# Generated by FakeRAM 2.0
VERSION 5.7 ;
BUSBITCHARS "[]" ;
PROPERTYDEFINITIONS
  MACRO width INTEGER ;
  MACRO depth INTEGER ;
  MACRO banks INTEGER ;
END PROPERTYDEFINITIONS
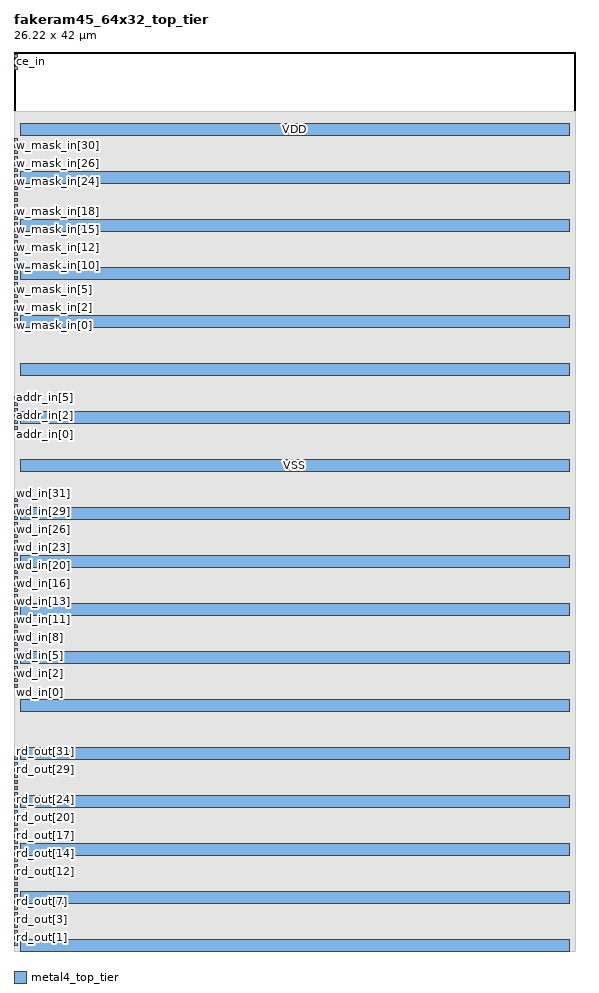
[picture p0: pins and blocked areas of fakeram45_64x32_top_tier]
MACRO fakeram45_64x32_top_tier
  PROPERTY width 32 ;
  PROPERTY depth 64 ;
  PROPERTY banks 1 ;
  FOREIGN fakeram45_64x32_top_tier 0 0 ;
  SYMMETRY X Y R90 ;
  SIZE 26.220 BY 42.0 ;
  CLASS BLOCK ;
  PIN rd_out[0]
    DIRECTION OUTPUT ;
    USE SIGNAL ;
    SHAPE ABUTMENT ;
    PORT
      LAYER metal4_top_tier ;
      RECT 0.000 0.280 0.140 0.420 ;
    END
  END rd_out[0]
  PIN rd_out[1]
    DIRECTION OUTPUT ;
    USE SIGNAL ;
    SHAPE ABUTMENT ;
    PORT
      LAYER metal4_top_tier ;
      RECT 0.000 0.560 0.140 0.700 ;
    END
  END rd_out[1]
  PIN rd_out[2]
    DIRECTION OUTPUT ;
    USE SIGNAL ;
    SHAPE ABUTMENT ;
    PORT
      LAYER metal4_top_tier ;
      RECT 0.000 0.840 0.140 0.980 ;
    END
  END rd_out[2]
  PIN rd_out[3]
    DIRECTION OUTPUT ;
    USE SIGNAL ;
    SHAPE ABUTMENT ;
    PORT
      LAYER metal4_top_tier ;
      RECT 0.000 1.120 0.140 1.260 ;
    END
  END rd_out[3]
  PIN rd_out[4]
    DIRECTION OUTPUT ;
    USE SIGNAL ;
    SHAPE ABUTMENT ;
    PORT
      LAYER metal4_top_tier ;
      RECT 0.000 1.400 0.140 1.540 ;
    END
  END rd_out[4]
  PIN rd_out[5]
    DIRECTION OUTPUT ;
    USE SIGNAL ;
    SHAPE ABUTMENT ;
    PORT
      LAYER metal4_top_tier ;
      RECT 0.000 1.680 0.140 1.820 ;
    END
  END rd_out[5]
  PIN rd_out[6]
    DIRECTION OUTPUT ;
    USE SIGNAL ;
    SHAPE ABUTMENT ;
    PORT
      LAYER metal4_top_tier ;
      RECT 0.000 1.960 0.140 2.100 ;
    END
  END rd_out[6]
  PIN rd_out[7]
    DIRECTION OUTPUT ;
    USE SIGNAL ;
    SHAPE ABUTMENT ;
    PORT
      LAYER metal4_top_tier ;
      RECT 0.000 2.240 0.140 2.380 ;
    END
  END rd_out[7]
  PIN rd_out[8]
    DIRECTION OUTPUT ;
    USE SIGNAL ;
    SHAPE ABUTMENT ;
    PORT
      LAYER metal4_top_tier ;
      RECT 0.000 2.520 0.140 2.660 ;
    END
  END rd_out[8]
  PIN rd_out[9]
    DIRECTION OUTPUT ;
    USE SIGNAL ;
    SHAPE ABUTMENT ;
    PORT
      LAYER metal4_top_tier ;
      RECT 0.000 2.800 0.140 2.940 ;
    END
  END rd_out[9]
  PIN rd_out[10]
    DIRECTION OUTPUT ;
    USE SIGNAL ;
    SHAPE ABUTMENT ;
    PORT
      LAYER metal4_top_tier ;
      RECT 0.000 3.080 0.140 3.220 ;
    END
  END rd_out[10]
  PIN rd_out[11]
    DIRECTION OUTPUT ;
    USE SIGNAL ;
    SHAPE ABUTMENT ;
    PORT
      LAYER metal4_top_tier ;
      RECT 0.000 3.360 0.140 3.500 ;
    END
  END rd_out[11]
  PIN rd_out[12]
    DIRECTION OUTPUT ;
    USE SIGNAL ;
    SHAPE ABUTMENT ;
    PORT
      LAYER metal4_top_tier ;
      RECT 0.000 3.640 0.140 3.780 ;
    END
  END rd_out[12]
  PIN rd_out[13]
    DIRECTION OUTPUT ;
    USE SIGNAL ;
    SHAPE ABUTMENT ;
    PORT
      LAYER metal4_top_tier ;
      RECT 0.000 3.920 0.140 4.060 ;
    END
  END rd_out[13]
  PIN rd_out[14]
    DIRECTION OUTPUT ;
    USE SIGNAL ;
    SHAPE ABUTMENT ;
    PORT
      LAYER metal4_top_tier ;
      RECT 0.000 4.200 0.140 4.340 ;
    END
  END rd_out[14]
  PIN rd_out[15]
    DIRECTION OUTPUT ;
    USE SIGNAL ;
    SHAPE ABUTMENT ;
    PORT
      LAYER metal4_top_tier ;
      RECT 0.000 4.480 0.140 4.620 ;
    END
  END rd_out[15]
  PIN rd_out[16]
    DIRECTION OUTPUT ;
    USE SIGNAL ;
    SHAPE ABUTMENT ;
    PORT
      LAYER metal4_top_tier ;
      RECT 0.000 4.760 0.140 4.900 ;
    END
  END rd_out[16]
  PIN rd_out[17]
    DIRECTION OUTPUT ;
    USE SIGNAL ;
    SHAPE ABUTMENT ;
    PORT
      LAYER metal4_top_tier ;
      RECT 0.000 5.040 0.140 5.180 ;
    END
  END rd_out[17]
  PIN rd_out[18]
    DIRECTION OUTPUT ;
    USE SIGNAL ;
    SHAPE ABUTMENT ;
    PORT
      LAYER metal4_top_tier ;
      RECT 0.000 5.320 0.140 5.460 ;
    END
  END rd_out[18]
  PIN rd_out[19]
    DIRECTION OUTPUT ;
    USE SIGNAL ;
    SHAPE ABUTMENT ;
    PORT
      LAYER metal4_top_tier ;
      RECT 0.000 5.600 0.140 5.740 ;
    END
  END rd_out[19]
  PIN rd_out[20]
    DIRECTION OUTPUT ;
    USE SIGNAL ;
    SHAPE ABUTMENT ;
    PORT
      LAYER metal4_top_tier ;
      RECT 0.000 5.880 0.140 6.020 ;
    END
  END rd_out[20]
  PIN rd_out[21]
    DIRECTION OUTPUT ;
    USE SIGNAL ;
    SHAPE ABUTMENT ;
    PORT
      LAYER metal4_top_tier ;
      RECT 0.000 6.160 0.140 6.300 ;
    END
  END rd_out[21]
  PIN rd_out[22]
    DIRECTION OUTPUT ;
    USE SIGNAL ;
    SHAPE ABUTMENT ;
    PORT
      LAYER metal4_top_tier ;
      RECT 0.000 6.440 0.140 6.580 ;
    END
  END rd_out[22]
  PIN rd_out[23]
    DIRECTION OUTPUT ;
    USE SIGNAL ;
    SHAPE ABUTMENT ;
    PORT
      LAYER metal4_top_tier ;
      RECT 0.000 6.720 0.140 6.860 ;
    END
  END rd_out[23]
  PIN rd_out[24]
    DIRECTION OUTPUT ;
    USE SIGNAL ;
    SHAPE ABUTMENT ;
    PORT
      LAYER metal4_top_tier ;
      RECT 0.000 7.000 0.140 7.140 ;
    END
  END rd_out[24]
  PIN rd_out[25]
    DIRECTION OUTPUT ;
    USE SIGNAL ;
    SHAPE ABUTMENT ;
    PORT
      LAYER metal4_top_tier ;
      RECT 0.000 7.280 0.140 7.420 ;
    END
  END rd_out[25]
  PIN rd_out[26]
    DIRECTION OUTPUT ;
    USE SIGNAL ;
    SHAPE ABUTMENT ;
    PORT
      LAYER metal4_top_tier ;
      RECT 0.000 7.560 0.140 7.700 ;
    END
  END rd_out[26]
  PIN rd_out[27]
    DIRECTION OUTPUT ;
    USE SIGNAL ;
    SHAPE ABUTMENT ;
    PORT
      LAYER metal4_top_tier ;
      RECT 0.000 7.840 0.140 7.980 ;
    END
  END rd_out[27]
  PIN rd_out[28]
    DIRECTION OUTPUT ;
    USE SIGNAL ;
    SHAPE ABUTMENT ;
    PORT
      LAYER metal4_top_tier ;
      RECT 0.000 8.120 0.140 8.260 ;
    END
  END rd_out[28]
  PIN rd_out[29]
    DIRECTION OUTPUT ;
    USE SIGNAL ;
    SHAPE ABUTMENT ;
    PORT
      LAYER metal4_top_tier ;
      RECT 0.000 8.400 0.140 8.540 ;
    END
  END rd_out[29]
  PIN rd_out[30]
    DIRECTION OUTPUT ;
    USE SIGNAL ;
    SHAPE ABUTMENT ;
    PORT
      LAYER metal4_top_tier ;
      RECT 0.000 8.680 0.140 8.820 ;
    END
  END rd_out[30]
  PIN rd_out[31]
    DIRECTION OUTPUT ;
    USE SIGNAL ;
    SHAPE ABUTMENT ;
    PORT
      LAYER metal4_top_tier ;
      RECT 0.000 8.960 0.140 9.100 ;
    END
  END rd_out[31]
  PIN wd_in[0]
    DIRECTION INPUT ;
    USE SIGNAL ;
    SHAPE ABUTMENT ;
    PORT
      LAYER metal4_top_tier ;
      RECT 0.000 12.320 0.140 12.460 ;
    END
  END wd_in[0]
  PIN wd_in[1]
    DIRECTION INPUT ;
    USE SIGNAL ;
    SHAPE ABUTMENT ;
    PORT
      LAYER metal4_top_tier ;
      RECT 0.000 12.600 0.140 12.740 ;
    END
  END wd_in[1]
  PIN wd_in[2]
    DIRECTION INPUT ;
    USE SIGNAL ;
    SHAPE ABUTMENT ;
    PORT
      LAYER metal4_top_tier ;
      RECT 0.000 12.880 0.140 13.020 ;
    END
  END wd_in[2]
  PIN wd_in[3]
    DIRECTION INPUT ;
    USE SIGNAL ;
    SHAPE ABUTMENT ;
    PORT
      LAYER metal4_top_tier ;
      RECT 0.000 13.160 0.140 13.300 ;
    END
  END wd_in[3]
  PIN wd_in[4]
    DIRECTION INPUT ;
    USE SIGNAL ;
    SHAPE ABUTMENT ;
    PORT
      LAYER metal4_top_tier ;
      RECT 0.000 13.440 0.140 13.580 ;
    END
  END wd_in[4]
  PIN wd_in[5]
    DIRECTION INPUT ;
    USE SIGNAL ;
    SHAPE ABUTMENT ;
    PORT
      LAYER metal4_top_tier ;
      RECT 0.000 13.720 0.140 13.860 ;
    END
  END wd_in[5]
  PIN wd_in[6]
    DIRECTION INPUT ;
    USE SIGNAL ;
    SHAPE ABUTMENT ;
    PORT
      LAYER metal4_top_tier ;
      RECT 0.000 14.000 0.140 14.140 ;
    END
  END wd_in[6]
  PIN wd_in[7]
    DIRECTION INPUT ;
    USE SIGNAL ;
    SHAPE ABUTMENT ;
    PORT
      LAYER metal4_top_tier ;
      RECT 0.000 14.280 0.140 14.420 ;
    END
  END wd_in[7]
  PIN wd_in[8]
    DIRECTION INPUT ;
    USE SIGNAL ;
    SHAPE ABUTMENT ;
    PORT
      LAYER metal4_top_tier ;
      RECT 0.000 14.560 0.140 14.700 ;
    END
  END wd_in[8]
  PIN wd_in[9]
    DIRECTION INPUT ;
    USE SIGNAL ;
    SHAPE ABUTMENT ;
    PORT
      LAYER metal4_top_tier ;
      RECT 0.000 14.840 0.140 14.980 ;
    END
  END wd_in[9]
  PIN wd_in[10]
    DIRECTION INPUT ;
    USE SIGNAL ;
    SHAPE ABUTMENT ;
    PORT
      LAYER metal4_top_tier ;
      RECT 0.000 15.120 0.140 15.260 ;
    END
  END wd_in[10]
  PIN wd_in[11]
    DIRECTION INPUT ;
    USE SIGNAL ;
    SHAPE ABUTMENT ;
    PORT
      LAYER metal4_top_tier ;
      RECT 0.000 15.400 0.140 15.540 ;
    END
  END wd_in[11]
  PIN wd_in[12]
    DIRECTION INPUT ;
    USE SIGNAL ;
    SHAPE ABUTMENT ;
    PORT
      LAYER metal4_top_tier ;
      RECT 0.000 15.680 0.140 15.820 ;
    END
  END wd_in[12]
  PIN wd_in[13]
    DIRECTION INPUT ;
    USE SIGNAL ;
    SHAPE ABUTMENT ;
    PORT
      LAYER metal4_top_tier ;
      RECT 0.000 15.960 0.140 16.100 ;
    END
  END wd_in[13]
  PIN wd_in[14]
    DIRECTION INPUT ;
    USE SIGNAL ;
    SHAPE ABUTMENT ;
    PORT
      LAYER metal4_top_tier ;
      RECT 0.000 16.240 0.140 16.380 ;
    END
  END wd_in[14]
  PIN wd_in[15]
    DIRECTION INPUT ;
    USE SIGNAL ;
    SHAPE ABUTMENT ;
    PORT
      LAYER metal4_top_tier ;
      RECT 0.000 16.520 0.140 16.660 ;
    END
  END wd_in[15]
  PIN wd_in[16]
    DIRECTION INPUT ;
    USE SIGNAL ;
    SHAPE ABUTMENT ;
    PORT
      LAYER metal4_top_tier ;
      RECT 0.000 16.800 0.140 16.940 ;
    END
  END wd_in[16]
  PIN wd_in[17]
    DIRECTION INPUT ;
    USE SIGNAL ;
    SHAPE ABUTMENT ;
    PORT
      LAYER metal4_top_tier ;
      RECT 0.000 17.080 0.140 17.220 ;
    END
  END wd_in[17]
  PIN wd_in[18]
    DIRECTION INPUT ;
    USE SIGNAL ;
    SHAPE ABUTMENT ;
    PORT
      LAYER metal4_top_tier ;
      RECT 0.000 17.360 0.140 17.500 ;
    END
  END wd_in[18]
  PIN wd_in[19]
    DIRECTION INPUT ;
    USE SIGNAL ;
    SHAPE ABUTMENT ;
    PORT
      LAYER metal4_top_tier ;
      RECT 0.000 17.640 0.140 17.780 ;
    END
  END wd_in[19]
  PIN wd_in[20]
    DIRECTION INPUT ;
    USE SIGNAL ;
    SHAPE ABUTMENT ;
    PORT
      LAYER metal4_top_tier ;
      RECT 0.000 17.920 0.140 18.060 ;
    END
  END wd_in[20]
  PIN wd_in[21]
    DIRECTION INPUT ;
    USE SIGNAL ;
    SHAPE ABUTMENT ;
    PORT
      LAYER metal4_top_tier ;
      RECT 0.000 18.200 0.140 18.340 ;
    END
  END wd_in[21]
  PIN wd_in[22]
    DIRECTION INPUT ;
    USE SIGNAL ;
    SHAPE ABUTMENT ;
    PORT
      LAYER metal4_top_tier ;
      RECT 0.000 18.480 0.140 18.620 ;
    END
  END wd_in[22]
  PIN wd_in[23]
    DIRECTION INPUT ;
    USE SIGNAL ;
    SHAPE ABUTMENT ;
    PORT
      LAYER metal4_top_tier ;
      RECT 0.000 18.760 0.140 18.900 ;
    END
  END wd_in[23]
  PIN wd_in[24]
    DIRECTION INPUT ;
    USE SIGNAL ;
    SHAPE ABUTMENT ;
    PORT
      LAYER metal4_top_tier ;
      RECT 0.000 19.040 0.140 19.180 ;
    END
  END wd_in[24]
  PIN wd_in[25]
    DIRECTION INPUT ;
    USE SIGNAL ;
    SHAPE ABUTMENT ;
    PORT
      LAYER metal4_top_tier ;
      RECT 0.000 19.320 0.140 19.460 ;
    END
  END wd_in[25]
  PIN wd_in[26]
    DIRECTION INPUT ;
    USE SIGNAL ;
    SHAPE ABUTMENT ;
    PORT
      LAYER metal4_top_tier ;
      RECT 0.000 19.600 0.140 19.740 ;
    END
  END wd_in[26]
  PIN wd_in[27]
    DIRECTION INPUT ;
    USE SIGNAL ;
    SHAPE ABUTMENT ;
    PORT
      LAYER metal4_top_tier ;
      RECT 0.000 19.880 0.140 20.020 ;
    END
  END wd_in[27]
  PIN wd_in[28]
    DIRECTION INPUT ;
    USE SIGNAL ;
    SHAPE ABUTMENT ;
    PORT
      LAYER metal4_top_tier ;
      RECT 0.000 20.160 0.140 20.300 ;
    END
  END wd_in[28]
  PIN wd_in[29]
    DIRECTION INPUT ;
    USE SIGNAL ;
    SHAPE ABUTMENT ;
    PORT
      LAYER metal4_top_tier ;
      RECT 0.000 20.440 0.140 20.580 ;
    END
  END wd_in[29]
  PIN wd_in[30]
    DIRECTION INPUT ;
    USE SIGNAL ;
    SHAPE ABUTMENT ;
    PORT
      LAYER metal4_top_tier ;
      RECT 0.000 20.720 0.140 20.860 ;
    END
  END wd_in[30]
  PIN wd_in[31]
    DIRECTION INPUT ;
    USE SIGNAL ;
    SHAPE ABUTMENT ;
    PORT
      LAYER metal4_top_tier ;
      RECT 0.000 21.000 0.140 21.140 ;
    END
  END wd_in[31]
  PIN addr_in[0]
    DIRECTION INPUT ;
    USE SIGNAL ;
    SHAPE ABUTMENT ;
    PORT
      LAYER metal4_top_tier ;
      RECT 0.000 24.360 0.140 24.500 ;
    END
  END addr_in[0]
  PIN addr_in[1]
    DIRECTION INPUT ;
    USE SIGNAL ;
    SHAPE ABUTMENT ;
    PORT
      LAYER metal4_top_tier ;
      RECT 0.000 24.640 0.140 24.780 ;
    END
  END addr_in[1]
  PIN addr_in[2]
    DIRECTION INPUT ;
    USE SIGNAL ;
    SHAPE ABUTMENT ;
    PORT
      LAYER metal4_top_tier ;
      RECT 0.000 24.920 0.140 25.060 ;
    END
  END addr_in[2]
  PIN addr_in[3]
    DIRECTION INPUT ;
    USE SIGNAL ;
    SHAPE ABUTMENT ;
    PORT
      LAYER metal4_top_tier ;
      RECT 0.000 25.200 0.140 25.340 ;
    END
  END addr_in[3]
  PIN addr_in[4]
    DIRECTION INPUT ;
    USE SIGNAL ;
    SHAPE ABUTMENT ;
    PORT
      LAYER metal4_top_tier ;
      RECT 0.000 25.480 0.140 25.620 ;
    END
  END addr_in[4]
  PIN addr_in[5]
    DIRECTION INPUT ;
    USE SIGNAL ;
    SHAPE ABUTMENT ;
    PORT
      LAYER metal4_top_tier ;
      RECT 0.000 25.760 0.140 25.900 ;
    END
  END addr_in[5]
  PIN w_mask_in[0]
    DIRECTION OUTPUT ;
    USE SIGNAL ;
    SHAPE ABUTMENT ;
    PORT
      LAYER metal4_top_tier ;
      RECT 0.000 29.120 0.140 29.260 ;
    END
  END w_mask_in[0]
  PIN w_mask_in[1]
    DIRECTION OUTPUT ;
    USE SIGNAL ;
    SHAPE ABUTMENT ;
    PORT
      LAYER metal4_top_tier ;
      RECT 0.000 29.400 0.140 29.540 ;
    END
  END w_mask_in[1]
  PIN w_mask_in[2]
    DIRECTION OUTPUT ;
    USE SIGNAL ;
    SHAPE ABUTMENT ;
    PORT
      LAYER metal4_top_tier ;
      RECT 0.000 29.680 0.140 29.820 ;
    END
  END w_mask_in[2]
  PIN w_mask_in[3]
    DIRECTION OUTPUT ;
    USE SIGNAL ;
    SHAPE ABUTMENT ;
    PORT
      LAYER metal4_top_tier ;
      RECT 0.000 29.960 0.140 30.100 ;
    END
  END w_mask_in[3]
  PIN w_mask_in[4]
    DIRECTION OUTPUT ;
    USE SIGNAL ;
    SHAPE ABUTMENT ;
    PORT
      LAYER metal4_top_tier ;
      RECT 0.000 30.240 0.140 30.380 ;
    END
  END w_mask_in[4]
  PIN w_mask_in[5]
    DIRECTION OUTPUT ;
    USE SIGNAL ;
    SHAPE ABUTMENT ;
    PORT
      LAYER metal4_top_tier ;
      RECT 0.000 30.520 0.140 30.660 ;
    END
  END w_mask_in[5]
  PIN w_mask_in[6]
    DIRECTION OUTPUT ;
    USE SIGNAL ;
    SHAPE ABUTMENT ;
    PORT
      LAYER metal4_top_tier ;
      RECT 0.000 30.800 0.140 30.940 ;
    END
  END w_mask_in[6]
  PIN w_mask_in[7]
    DIRECTION OUTPUT ;
    USE SIGNAL ;
    SHAPE ABUTMENT ;
    PORT
      LAYER metal4_top_tier ;
      RECT 0.000 31.080 0.140 31.220 ;
    END
  END w_mask_in[7]
  PIN w_mask_in[8]
    DIRECTION OUTPUT ;
    USE SIGNAL ;
    SHAPE ABUTMENT ;
    PORT
      LAYER metal4_top_tier ;
      RECT 0.000 31.360 0.140 31.500 ;
    END
  END w_mask_in[8]
  PIN w_mask_in[9]
    DIRECTION OUTPUT ;
    USE SIGNAL ;
    SHAPE ABUTMENT ;
    PORT
      LAYER metal4_top_tier ;
      RECT 0.000 31.640 0.140 31.780 ;
    END
  END w_mask_in[9]
  PIN w_mask_in[10]
    DIRECTION OUTPUT ;
    USE SIGNAL ;
    SHAPE ABUTMENT ;
    PORT
      LAYER metal4_top_tier ;
      RECT 0.000 31.920 0.140 32.060 ;
    END
  END w_mask_in[10]
  PIN w_mask_in[11]
    DIRECTION OUTPUT ;
    USE SIGNAL ;
    SHAPE ABUTMENT ;
    PORT
      LAYER metal4_top_tier ;
      RECT 0.000 32.200 0.140 32.340 ;
    END
  END w_mask_in[11]
  PIN w_mask_in[12]
    DIRECTION OUTPUT ;
    USE SIGNAL ;
    SHAPE ABUTMENT ;
    PORT
      LAYER metal4_top_tier ;
      RECT 0.000 32.480 0.140 32.620 ;
    END
  END w_mask_in[12]
  PIN w_mask_in[13]
    DIRECTION OUTPUT ;
    USE SIGNAL ;
    SHAPE ABUTMENT ;
    PORT
      LAYER metal4_top_tier ;
      RECT 0.000 32.760 0.140 32.900 ;
    END
  END w_mask_in[13]
  PIN w_mask_in[14]
    DIRECTION OUTPUT ;
    USE SIGNAL ;
    SHAPE ABUTMENT ;
    PORT
      LAYER metal4_top_tier ;
      RECT 0.000 33.040 0.140 33.180 ;
    END
  END w_mask_in[14]
  PIN w_mask_in[15]
    DIRECTION OUTPUT ;
    USE SIGNAL ;
    SHAPE ABUTMENT ;
    PORT
      LAYER metal4_top_tier ;
      RECT 0.000 33.320 0.140 33.460 ;
    END
  END w_mask_in[15]
  PIN w_mask_in[16]
    DIRECTION OUTPUT ;
    USE SIGNAL ;
    SHAPE ABUTMENT ;
    PORT
      LAYER metal4_top_tier ;
      RECT 0.000 33.600 0.140 33.740 ;
    END
  END w_mask_in[16]
  PIN w_mask_in[17]
    DIRECTION OUTPUT ;
    USE SIGNAL ;
    SHAPE ABUTMENT ;
    PORT
      LAYER metal4_top_tier ;
      RECT 0.000 33.880 0.140 34.020 ;
    END
  END w_mask_in[17]
  PIN w_mask_in[18]
    DIRECTION OUTPUT ;
    USE SIGNAL ;
    SHAPE ABUTMENT ;
    PORT
      LAYER metal4_top_tier ;
      RECT 0.000 34.160 0.140 34.300 ;
    END
  END w_mask_in[18]
  PIN w_mask_in[19]
    DIRECTION OUTPUT ;
    USE SIGNAL ;
    SHAPE ABUTMENT ;
    PORT
      LAYER metal4_top_tier ;
      RECT 0.000 34.440 0.140 34.580 ;
    END
  END w_mask_in[19]
  PIN w_mask_in[20]
    DIRECTION OUTPUT ;
    USE SIGNAL ;
    SHAPE ABUTMENT ;
    PORT
      LAYER metal4_top_tier ;
      RECT 0.000 34.720 0.140 34.860 ;
    END
  END w_mask_in[20]
  PIN w_mask_in[21]
    DIRECTION OUTPUT ;
    USE SIGNAL ;
    SHAPE ABUTMENT ;
    PORT
      LAYER metal4_top_tier ;
      RECT 0.000 35.000 0.140 35.140 ;
    END
  END w_mask_in[21]
  PIN w_mask_in[22]
    DIRECTION OUTPUT ;
    USE SIGNAL ;
    SHAPE ABUTMENT ;
    PORT
      LAYER metal4_top_tier ;
      RECT 0.000 35.280 0.140 35.420 ;
    END
  END w_mask_in[22]
  PIN w_mask_in[23]
    DIRECTION OUTPUT ;
    USE SIGNAL ;
    SHAPE ABUTMENT ;
    PORT
      LAYER metal4_top_tier ;
      RECT 0.000 35.560 0.140 35.700 ;
    END
  END w_mask_in[23]
  PIN w_mask_in[24]
    DIRECTION OUTPUT ;
    USE SIGNAL ;
    SHAPE ABUTMENT ;
    PORT
      LAYER metal4_top_tier ;
      RECT 0.000 35.840 0.140 35.980 ;
    END
  END w_mask_in[24]
  PIN w_mask_in[25]
    DIRECTION OUTPUT ;
    USE SIGNAL ;
    SHAPE ABUTMENT ;
    PORT
      LAYER metal4_top_tier ;
      RECT 0.000 36.120 0.140 36.260 ;
    END
  END w_mask_in[25]
  PIN w_mask_in[26]
    DIRECTION OUTPUT ;
    USE SIGNAL ;
    SHAPE ABUTMENT ;
    PORT
      LAYER metal4_top_tier ;
      RECT 0.000 36.400 0.140 36.540 ;
    END
  END w_mask_in[26]
  PIN w_mask_in[27]
    DIRECTION OUTPUT ;
    USE SIGNAL ;
    SHAPE ABUTMENT ;
    PORT
      LAYER metal4_top_tier ;
      RECT 0.000 36.680 0.140 36.820 ;
    END
  END w_mask_in[27]
  PIN w_mask_in[28]
    DIRECTION OUTPUT ;
    USE SIGNAL ;
    SHAPE ABUTMENT ;
    PORT
      LAYER metal4_top_tier ;
      RECT 0.000 36.960 0.140 37.100 ;
    END
  END w_mask_in[28]
  PIN w_mask_in[29]
    DIRECTION OUTPUT ;
    USE SIGNAL ;
    SHAPE ABUTMENT ;
    PORT
      LAYER metal4_top_tier ;
      RECT 0.000 37.240 0.140 37.380 ;
    END
  END w_mask_in[29]
  PIN w_mask_in[30]
    DIRECTION OUTPUT ;
    USE SIGNAL ;
    SHAPE ABUTMENT ;
    PORT
      LAYER metal4_top_tier ;
      RECT 0.000 37.520 0.140 37.660 ;
    END
  END w_mask_in[30]
  PIN w_mask_in[31]
    DIRECTION OUTPUT ;
    USE SIGNAL ;
    SHAPE ABUTMENT ;
    PORT
      LAYER metal4_top_tier ;
      RECT 0.000 37.800 0.140 37.940 ;
    END
  END w_mask_in[31]
  PIN we_in
    DIRECTION INPUT ;
    USE SIGNAL ;
    SHAPE ABUTMENT ;
    PORT
      LAYER metal4_top_tier ;
      RECT 0.000 41.160 0.140 41.300 ;
    END
  END we_in
  PIN ce_in
    DIRECTION INPUT ;
    USE SIGNAL ;
    SHAPE ABUTMENT ;
    PORT
      LAYER metal4_top_tier ;
      RECT 0.000 41.440 0.140 41.580 ;
    END
  END ce_in
  PIN clk
    DIRECTION INPUT ;
    USE SIGNAL ;
    SHAPE ABUTMENT ;
    PORT
      LAYER metal4_top_tier ;
      RECT 0.000 41.720 0.140 41.860 ;
    END
  END clk
  PIN VSS
    DIRECTION INOUT ;
    USE GROUND ;
    PORT
      LAYER metal4_top_tier ;
      RECT 0.280 0.000 25.940 0.560 ;
      RECT 0.280 4.480 25.940 5.040 ;
      RECT 0.280 8.960 25.940 9.520 ;
      RECT 0.280 13.440 25.940 14.000 ;
      RECT 0.280 17.920 25.940 18.480 ;
      RECT 0.280 22.400 25.940 22.960 ;
      RECT 0.280 26.880 25.940 27.440 ;
      RECT 0.280 31.360 25.940 31.920 ;
      RECT 0.280 35.840 25.940 36.400 ;
    END
  END VSS
  PIN VDD
    DIRECTION INOUT ;
    USE POWER ;
    PORT
      LAYER metal4_top_tier ;
      RECT 0.280 2.240 25.940 2.800 ;
      RECT 0.280 6.720 25.940 7.280 ;
      RECT 0.280 11.200 25.940 11.760 ;
      RECT 0.280 15.680 25.940 16.240 ;
      RECT 0.280 20.160 25.940 20.720 ;
      RECT 0.280 24.640 25.940 25.200 ;
      RECT 0.280 29.120 25.940 29.680 ;
      RECT 0.280 33.600 25.940 34.160 ;
      RECT 0.280 38.080 25.940 38.640 ;
    END
  END VDD
  OBS
    LAYER metal1_top_tier ;
    RECT 0 0 26.220 39.200 ;
    LAYER metal2_top_tier ;
    RECT 0 0 26.220 39.200 ;
    LAYER metal3_top_tier ;
    RECT 0 0 26.220 39.200 ;
    LAYER metal4_top_tier ;
    RECT 0 0 26.220 39.200 ;
  END
END fakeram45_64x32_top_tier

END LIBRARY
